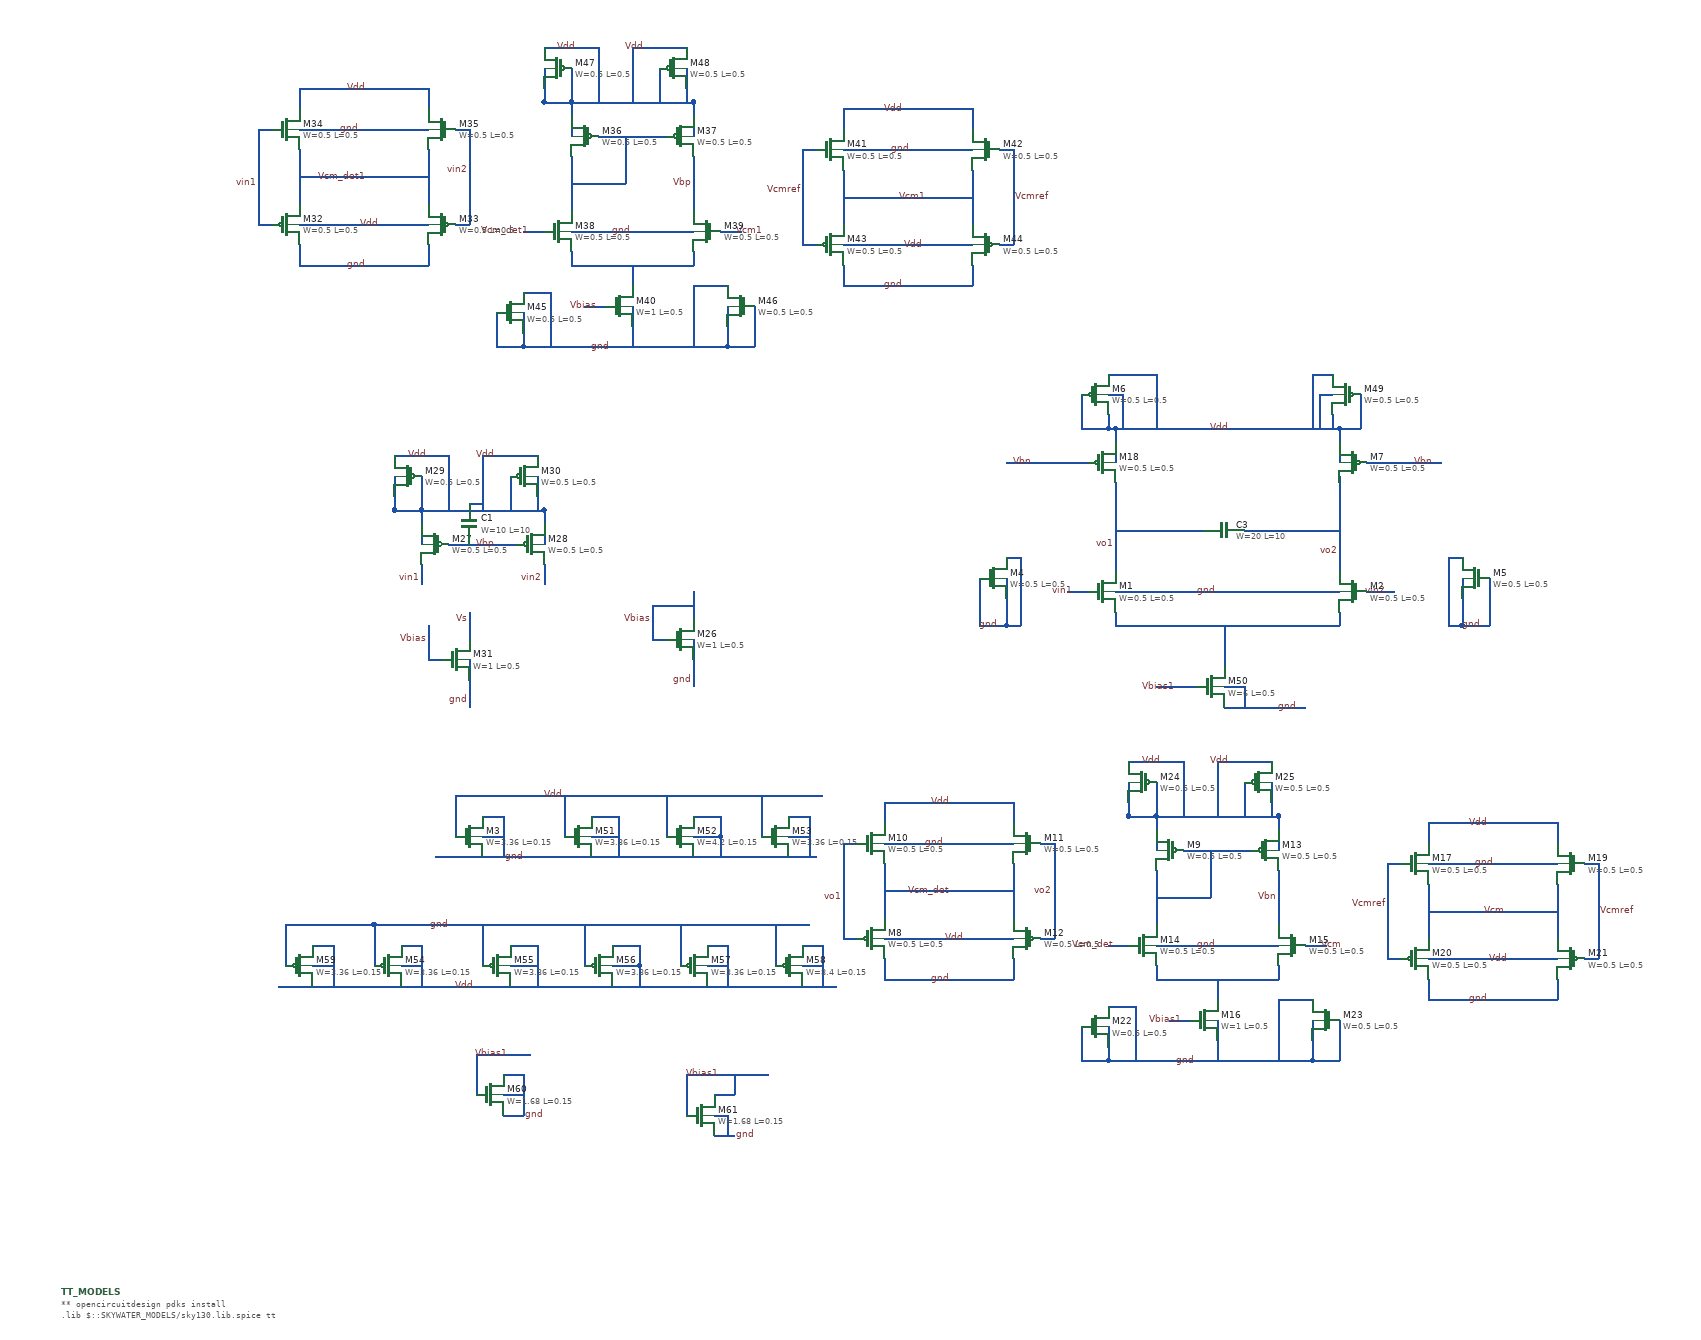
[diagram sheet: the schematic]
v {xschem version=3.4.4 file_version=1.2
}
G {}
K {}
V {}
S {}
E {}
N -2610 -900 -2610 -860 {
lab=Vbias}
N -2670 -830 -2650 -830 {
lab=Vbias}
N -2670 -880 -2670 -830 {
lab=Vbias}
N -2670 -880 -2610 -880 {
lab=Vbias}
N -2610 -800 -2610 -760 {
lab=gnd}
N -2610 -830 -2610 -790 {
lab=gnd}
N -3010 -1020 -3010 -1000 {
lab=Vdd}
N -2830 -1020 -2830 -1000 {
lab=Vdd}
N -2970 -970 -2870 -970 {
lab=Vbp}
N -3010 -1020 -2830 -1020 {
lab=Vdd}
N -3050 -1040 -3050 -1020 {
lab=Vdd}
N -3050 -1020 -2990 -1020 {
lab=Vdd}
N -2840 -1040 -2840 -1020 {
lab=Vdd}
N -3010 -1070 -3010 -1020 {
lab=Vdd}
N -2880 -1070 -2880 -1020 {
lab=Vdd}
N -3050 -1100 -2970 -1100 {
lab=Vdd}
N -2970 -1100 -2970 -1020 {
lab=Vdd}
N -2920 -1100 -2840 -1100 {
lab=Vdd}
N -2920 -1100 -2920 -1020 {
lab=Vdd}
N -3010 -1010 -3010 -970 {
lab=Vdd}
N -2830 -1020 -2830 -970 {
lab=Vdd}
N -3050 -1070 -3050 -1020 {
lab=Vdd}
N -2840 -1070 -2840 -1030 {
lab=Vdd}
N -3010 -940 -3010 -910 {
lab=vin1}
N -2830 -940 -2830 -910 {
lab=vin2}
N -2940 -870 -2940 -830 {
lab=Vs}
N -3000 -800 -2980 -800 {
lab=Vbias}
N -3000 -850 -3000 -800 {
lab=Vbias}
N -2940 -770 -2940 -730 {
lab=gnd}
N -2940 -800 -2940 -760 {
lab=gnd}
N -2940 -1030 -2920 -1030 {
lab=Vdd}
N -2790 -1540 -2790 -1460 {
lab=#net1}
N -2610 -1540 -2610 -1460 {
lab=Vbp}
N -2790 -1620 -2790 -1600 {
lab=Vdd}
N -2610 -1620 -2610 -1600 {
lab=Vdd}
N -2790 -1400 -2790 -1380 {
lab=#net2}
N -2790 -1380 -2610 -1380 {
lab=#net2}
N -2610 -1400 -2610 -1380 {
lab=#net2}
N -2750 -1570 -2650 -1570 {
lab=#net1}
N -2710 -1570 -2710 -1500 {
lab=#net1}
N -2790 -1500 -2710 -1500 {
lab=#net1}
N -3190 -1640 -3190 -1610 {
lab=Vdd}
N -3190 -1640 -3000 -1640 {
lab=Vdd}
N -3000 -1640 -3000 -1610 {
lab=Vdd}
N -3190 -1550 -3190 -1470 {
lab=Vcm_det1}
N -3000 -1550 -3000 -1470 {
lab=Vcm_det1}
N -3250 -1580 -3230 -1580 {
lab=vin1}
N -3250 -1580 -3250 -1440 {
lab=vin1}
N -3250 -1440 -3230 -1440 {
lab=vin1}
N -2960 -1580 -2940 -1580 {
lab=vin2}
N -2940 -1580 -2940 -1440 {
lab=vin2}
N -2960 -1440 -2940 -1440 {
lab=vin2}
N -2390 -1610 -2390 -1580 {
lab=Vdd}
N -2390 -1610 -2200 -1610 {
lab=Vdd}
N -2200 -1610 -2200 -1580 {
lab=Vdd}
N -2390 -1520 -2390 -1440 {
lab=Vcm1}
N -2200 -1520 -2200 -1440 {
lab=Vcm1}
N -2390 -1380 -2390 -1350 {
lab=gnd}
N -2200 -1380 -2200 -1350 {
lab=gnd}
N -2450 -1550 -2430 -1550 {
lab=Vcmref}
N -2450 -1550 -2450 -1410 {
lab=Vcmref}
N -2450 -1410 -2430 -1410 {
lab=Vcmref}
N -2160 -1550 -2140 -1550 {
lab=Vcmref}
N -2140 -1550 -2140 -1410 {
lab=Vcmref}
N -2160 -1410 -2140 -1410 {
lab=Vcmref}
N -2700 -1380 -2700 -1350 {
lab=#net2}
N -2700 -1290 -2700 -1260 {
lab=gnd}
N -3190 -1510 -3000 -1510 {
lab=Vcm_det1}
N -2390 -1480 -2200 -1480 {
lab=Vcm1}
N -2860 -1430 -2830 -1430 {
lab=Vcm_det1}
N -2570 -1430 -2540 -1430 {
lab=Vcm1}
N -2790 -1620 -2610 -1620 {
lab=Vdd}
N -2390 -1350 -2200 -1350 {
lab=gnd}
N -2860 -1280 -2860 -1260 {
lab=gnd}
N -2860 -1260 -2560 -1260 {
lab=gnd}
N -2560 -1290 -2560 -1260 {
lab=gnd}
N -2900 -1310 -2900 -1260 {
lab=gnd}
N -2900 -1260 -2860 -1260 {
lab=gnd}
N -2860 -1340 -2820 -1340 {
lab=gnd}
N -2820 -1340 -2820 -1260 {
lab=gnd}
N -2520 -1320 -2520 -1260 {
lab=gnd}
N -2560 -1260 -2520 -1260 {
lab=gnd}
N -2610 -1350 -2560 -1350 {
lab=gnd}
N -2610 -1350 -2610 -1260 {
lab=gnd}
N -2830 -1640 -2830 -1620 {
lab=Vdd}
N -2830 -1620 -2770 -1620 {
lab=Vdd}
N -2620 -1640 -2620 -1620 {
lab=Vdd}
N -2790 -1670 -2790 -1620 {
lab=Vdd}
N -2660 -1670 -2660 -1620 {
lab=Vdd}
N -2830 -1700 -2750 -1700 {
lab=Vdd}
N -2750 -1700 -2750 -1620 {
lab=Vdd}
N -2700 -1700 -2620 -1700 {
lab=Vdd}
N -2700 -1700 -2700 -1620 {
lab=Vdd}
N -3190 -1410 -3190 -1380 {
lab=gnd}
N -3190 -1380 -3000 -1380 {
lab=gnd}
N -3000 -1410 -3000 -1380 {
lab=gnd}
N -2790 -1610 -2790 -1570 {
lab=Vdd}
N -2610 -1620 -2610 -1570 {
lab=Vdd}
N -2830 -1670 -2830 -1620 {
lab=Vdd}
N -2620 -1670 -2620 -1630 {
lab=Vdd}
N -2860 -1310 -2860 -1270 {
lab=gnd}
N -2560 -1320 -2560 -1280 {
lab=gnd}
N -2700 -1320 -2700 -1280 {
lab=gnd}
N -3190 -1580 -3140 -1580 {
lab=gnd}
N -3070 -1580 -3000 -1580 {
lab=gnd}
N -3140 -1580 -3070 -1580 {
lab=gnd}
N -3190 -1440 -3000 -1440 {
lab=Vdd}
N -2390 -1550 -2200 -1550 {
lab=gnd}
N -2390 -1410 -2200 -1410 {
lab=Vdd}
N -2790 -1430 -2610 -1430 {
lab=gnd}
N -2770 -1320 -2740 -1320 {
lab=Vbias}
N -1990 -870 -1990 -850 {
lab=#net3}
N -1990 -850 -1810 -850 {
lab=#net3}
N -1660 -870 -1660 -850 {
lab=#net3}
N -1990 -1140 -1990 -1120 {
lab=Vdd}
N -1990 -1140 -1810 -1140 {
lab=Vdd}
N -1660 -1140 -1660 -1120 {
lab=Vdd}
N -1810 -1140 -1660 -1140 {
lab=Vdd}
N -1810 -850 -1660 -850 {
lab=#net3}
N -1990 -990 -1860 -990 {
lab=vo1}
N -1800 -990 -1660 -990 {
lab=vo2}
N -2150 -1090 -2030 -1090 {
lab=Vbn}
N -1620 -1090 -1510 -1090 {
lab=Vbn}
N -2060 -900 -2030 -900 {
lab=vin1}
N -1620 -900 -1580 -900 {
lab=vin2}
N -1990 -1000 -1990 -930 {
lab=vo1}
N -1660 -1000 -1660 -930 {
lab=vo2}
N -1660 -1070 -1660 -1000 {
lab=vo2}
N -1990 -1060 -1990 -1000 {
lab=vo1}
N -1830 -850 -1830 -790 {
lab=#net3}
N -2150 -890 -2150 -850 {
lab=gnd}
N -1480 -890 -1480 -850 {
lab=gnd}
N -2190 -920 -2190 -850 {
lab=gnd}
N -2190 -850 -2150 -850 {
lab=gnd}
N -2150 -950 -2130 -950 {
lab=gnd}
N -2130 -950 -2130 -850 {
lab=gnd}
N -2150 -920 -2150 -870 {
lab=gnd}
N -1500 -950 -1480 -950 {
lab=gnd}
N -1500 -950 -1500 -850 {
lab=gnd}
N -1480 -920 -1480 -870 {
lab=gnd}
N -1440 -920 -1440 -850 {
lab=gnd}
N -1480 -850 -1440 -850 {
lab=gnd}
N -2000 -1160 -2000 -1140 {
lab=Vdd}
N -2000 -1140 -1990 -1140 {
lab=Vdd}
N -1670 -1160 -1670 -1140 {
lab=Vdd}
N -2000 -1220 -1930 -1220 {
lab=Vdd}
N -1930 -1220 -1930 -1140 {
lab=Vdd}
N -1700 -1220 -1670 -1220 {
lab=Vdd}
N -1700 -1220 -1700 -1140 {
lab=Vdd}
N -2000 -1190 -1980 -1190 {
lab=Vdd}
N -1980 -1190 -1980 -1140 {
lab=Vdd}
N -1690 -1190 -1670 -1190 {
lab=Vdd}
N -1690 -1190 -1690 -1140 {
lab=Vdd}
N -1630 -1190 -1630 -1140 {
lab=Vdd}
N -1660 -1140 -1630 -1140 {
lab=Vdd}
N -2040 -1190 -2040 -1140 {
lab=Vdd}
N -2040 -1140 -2000 -1140 {
lab=Vdd}
N -1990 -1130 -1990 -1090 {
lab=Vdd}
N -1660 -1130 -1660 -1090 {
lab=Vdd}
N -1930 -490 -1930 -410 {
lab=#net4}
N -1750 -490 -1750 -410 {
lab=Vbn}
N -1930 -570 -1930 -550 {
lab=Vdd}
N -1750 -570 -1750 -550 {
lab=Vdd}
N -1930 -350 -1930 -330 {
lab=#net5}
N -1930 -330 -1750 -330 {
lab=#net5}
N -1750 -350 -1750 -330 {
lab=#net5}
N -1890 -520 -1790 -520 {
lab=#net4}
N -1850 -520 -1850 -450 {
lab=#net4}
N -1930 -450 -1850 -450 {
lab=#net4}
N -2330 -590 -2330 -560 {
lab=Vdd}
N -2330 -590 -2140 -590 {
lab=Vdd}
N -2140 -590 -2140 -560 {
lab=Vdd}
N -2330 -500 -2330 -420 {
lab=Vcm_det}
N -2140 -500 -2140 -420 {
lab=Vcm_det}
N -2390 -530 -2370 -530 {
lab=vo1}
N -2390 -530 -2390 -390 {
lab=vo1}
N -2390 -390 -2370 -390 {
lab=vo1}
N -2100 -530 -2080 -530 {
lab=vo2}
N -2080 -530 -2080 -390 {
lab=vo2}
N -2100 -390 -2080 -390 {
lab=vo2}
N -1530 -560 -1530 -530 {
lab=Vdd}
N -1530 -560 -1340 -560 {
lab=Vdd}
N -1340 -560 -1340 -530 {
lab=Vdd}
N -1530 -470 -1530 -390 {
lab=Vcm}
N -1340 -470 -1340 -390 {
lab=Vcm}
N -1530 -330 -1530 -300 {
lab=gnd}
N -1340 -330 -1340 -300 {
lab=gnd}
N -1590 -500 -1570 -500 {
lab=Vcmref}
N -1590 -500 -1590 -360 {
lab=Vcmref}
N -1590 -360 -1570 -360 {
lab=Vcmref}
N -1300 -500 -1280 -500 {
lab=Vcmref}
N -1280 -500 -1280 -360 {
lab=Vcmref}
N -1300 -360 -1280 -360 {
lab=Vcmref}
N -1840 -330 -1840 -300 {
lab=#net5}
N -1840 -240 -1840 -210 {
lab=gnd}
N -2330 -460 -2140 -460 {
lab=Vcm_det}
N -1530 -430 -1340 -430 {
lab=Vcm}
N -2000 -380 -1970 -380 {
lab=Vcm_det}
N -1710 -380 -1680 -380 {
lab=Vcm}
N -1930 -570 -1750 -570 {
lab=Vdd}
N -1530 -300 -1340 -300 {
lab=gnd}
N -2000 -230 -2000 -210 {
lab=gnd}
N -2000 -210 -1700 -210 {
lab=gnd}
N -1700 -240 -1700 -210 {
lab=gnd}
N -2040 -260 -2040 -210 {
lab=gnd}
N -2040 -210 -2000 -210 {
lab=gnd}
N -2000 -290 -1960 -290 {
lab=gnd}
N -1960 -290 -1960 -210 {
lab=gnd}
N -1660 -270 -1660 -210 {
lab=gnd}
N -1700 -210 -1660 -210 {
lab=gnd}
N -1750 -300 -1700 -300 {
lab=gnd}
N -1750 -300 -1750 -210 {
lab=gnd}
N -1970 -590 -1970 -570 {
lab=Vdd}
N -1970 -570 -1910 -570 {
lab=Vdd}
N -1760 -590 -1760 -570 {
lab=Vdd}
N -1930 -620 -1930 -570 {
lab=Vdd}
N -1800 -620 -1800 -570 {
lab=Vdd}
N -1970 -650 -1890 -650 {
lab=Vdd}
N -1890 -650 -1890 -570 {
lab=Vdd}
N -1840 -650 -1760 -650 {
lab=Vdd}
N -1840 -650 -1840 -570 {
lab=Vdd}
N -2330 -360 -2330 -330 {
lab=gnd}
N -2330 -330 -2140 -330 {
lab=gnd}
N -2140 -360 -2140 -330 {
lab=gnd}
N -1930 -560 -1930 -520 {
lab=Vdd}
N -1750 -570 -1750 -520 {
lab=Vdd}
N -1970 -620 -1970 -570 {
lab=Vdd}
N -1760 -620 -1760 -580 {
lab=Vdd}
N -2000 -260 -2000 -220 {
lab=gnd}
N -1700 -270 -1700 -230 {
lab=gnd}
N -1840 -270 -1840 -230 {
lab=gnd}
N -2330 -530 -2280 -530 {
lab=gnd}
N -2210 -530 -2140 -530 {
lab=gnd}
N -2280 -530 -2210 -530 {
lab=gnd}
N -2330 -390 -2140 -390 {
lab=Vdd}
N -1530 -500 -1340 -500 {
lab=gnd}
N -1530 -360 -1340 -360 {
lab=Vdd}
N -1930 -380 -1750 -380 {
lab=gnd}
N -1910 -270 -1880 -270 {
lab=Vbias1}
N -1990 -900 -1660 -900 {
lab=gnd}
N -1830 -730 -1710 -730 {
lab=gnd}
N -1830 -760 -1800 -760 {
lab=gnd}
N -1800 -760 -1800 -730 {
lab=gnd}
N -1930 -760 -1870 -760 {
lab=Vbias1}
N -2150 -850 -2130 -850 {
lab=gnd}
N -1500 -850 -1480 -850 {
lab=gnd}
N -2920 -570 -2890 -570 {
lab=gnd}
N -2890 -570 -2890 -510 {
lab=gnd}
N -2920 -510 -2890 -510 {
lab=gnd}
N -2920 -540 -2890 -540 {
lab=gnd}
N -2990 -510 -2540 -510 {
lab=gnd}
N -2960 -570 -2960 -540 {
lab=Vdd}
N -2800 -570 -2800 -540 {
lab=Vdd}
N -2960 -600 -2960 -570 {
lab=Vdd}
N -2960 -600 -2540 -600 {
lab=Vdd}
N -2800 -600 -2800 -570 {
lab=Vdd}
N -2760 -570 -2720 -570 {
lab=gnd}
N -2720 -570 -2720 -510 {
lab=gnd}
N -2760 -540 -2720 -540 {
lab=gnd}
N -2650 -600 -2650 -540 {
lab=Vdd}
N -2610 -540 -2570 -540 {
lab=gnd}
N -2570 -540 -2570 -510 {
lab=gnd}
N -2610 -570 -2570 -570 {
lab=gnd}
N -2570 -570 -2570 -540 {
lab=gnd}
N -2540 -600 -2420 -600 {
lab=Vdd}
N -2540 -510 -2430 -510 {
lab=gnd}
N -2510 -600 -2510 -540 {
lab=Vdd}
N -2470 -570 -2440 -570 {
lab=gnd}
N -2440 -570 -2440 -510 {
lab=gnd}
N -2470 -540 -2440 -540 {
lab=gnd}
N -3040 -380 -3010 -380 {
lab=Vdd}
N -3010 -380 -3010 -320 {
lab=Vdd}
N -3040 -320 -3010 -320 {
lab=Vdd}
N -3040 -350 -3010 -350 {
lab=Vdd}
N -3110 -320 -2660 -320 {
lab=Vdd}
N -3080 -380 -3080 -350 {
lab=gnd}
N -2920 -380 -2920 -350 {
lab=gnd}
N -3080 -410 -3080 -380 {
lab=gnd}
N -3080 -410 -2660 -410 {
lab=gnd}
N -2920 -410 -2920 -380 {
lab=gnd}
N -2880 -380 -2840 -380 {
lab=Vdd}
N -2840 -380 -2840 -320 {
lab=Vdd}
N -2880 -350 -2840 -350 {
lab=Vdd}
N -2770 -410 -2770 -350 {
lab=gnd}
N -2730 -350 -2690 -350 {
lab=Vdd}
N -2690 -350 -2690 -320 {
lab=Vdd}
N -2730 -380 -2690 -380 {
lab=Vdd}
N -2690 -380 -2690 -350 {
lab=Vdd}
N -2660 -410 -2540 -410 {
lab=gnd}
N -2660 -320 -2550 -320 {
lab=Vdd}
N -2630 -410 -2630 -350 {
lab=gnd}
N -2590 -380 -2560 -380 {
lab=Vdd}
N -2560 -380 -2560 -320 {
lab=Vdd}
N -2590 -350 -2560 -350 {
lab=Vdd}
N -2540 -410 -2440 -410 {
lab=gnd}
N -2550 -320 -2400 -320 {
lab=Vdd}
N -2450 -380 -2420 -380 {
lab=Vdd}
N -2420 -380 -2420 -320 {
lab=Vdd}
N -2450 -350 -2420 -350 {
lab=Vdd}
N -2490 -410 -2490 -350 {
lab=gnd}
N -3210 -410 -3080 -410 {
lab=gnd}
N -3220 -320 -3110 -320 {
lab=Vdd}
N -3210 -410 -3210 -350 {
lab=gnd}
N -3170 -380 -3140 -380 {
lab=Vdd}
N -3140 -380 -3140 -320 {
lab=Vdd}
N -3170 -350 -3140 -350 {
lab=Vdd}
N -2890 -190 -2860 -190 {
lab=gnd}
N -2860 -190 -2860 -130 {
lab=gnd}
N -2890 -130 -2860 -130 {
lab=gnd}
N -2890 -160 -2860 -160 {
lab=gnd}
N -2930 -190 -2930 -160 {
lab=Vbias1}
N -2930 -220 -2930 -190 {
lab=Vbias1}
N -2930 -220 -2850 -220 {
lab=Vbias1}
N -2580 -160 -2550 -160 {
lab=gnd}
N -2580 -100 -2550 -100 {
lab=gnd}
N -2620 -160 -2620 -130 {
lab=Vbias1}
N -2620 -190 -2620 -160 {
lab=Vbias1}
N -2620 -190 -2540 -190 {
lab=Vbias1}
N -2580 -130 -2560 -130 {}
N -2560 -130 -2560 -100 {}
N -2550 -190 -2550 -160 {}
N -2540 -190 -2500 -190 {}
C {devices/code.sym} -3540 130 0 0 {name=TT_MODELS
only_toplevel=true
format="tcleval( @value )"
value="
** opencircuitdesign pdks install
.lib $::SKYWATER_MODELS/sky130.lib.spice tt

"
spice_ignore=false}
C {devices/lab_wire.sym} -2670 -860 0 0 {name=p30 sig_type=std_logic lab=Vbias

}
C {sky130_fd_pr/nfet_01v8.sym} -2630 -830 0 0 {name=M26
L=0.5
W=1
nf=1 
mult=1
ad="'int((nf+1)/2) * W/nf * 0.29'" 
pd="'2*int((nf+1)/2) * (W/nf + 0.29)'"
as="'int((nf+2)/2) * W/nf * 0.29'" 
ps="'2*int((nf+2)/2) * (W/nf + 0.29)'"
nrd="'0.29 / W'" nrs="'0.29 / W'"
sa=0 sb=0 sd=0
model=nfet_01v8
spiceprefix=X
}
C {devices/lab_wire.sym} -2610 -770 0 0 {name=p31 sig_type=std_logic lab=gnd

}
C {sky130_fd_pr/pfet_01v8.sym} -2990 -970 0 1 {name=M27
L=0.5
W=0.5
nf=1
mult=1
ad="'int((nf+1)/2) * W/nf * 0.29'" 
pd="'2*int((nf+1)/2) * (W/nf + 0.29)'"
as="'int((nf+2)/2) * W/nf * 0.29'" 
ps="'2*int((nf+2)/2) * (W/nf + 0.29)'"
nrd="'0.29 / W'" nrs="'0.29 / W'"
sa=0 sb=0 sd=0
model=pfet_01v8
spiceprefix=X
}
C {sky130_fd_pr/pfet_01v8.sym} -2850 -970 0 0 {name=M28
L=0.5
W=0.5
nf=1
mult=1
ad="'int((nf+1)/2) * W/nf * 0.29'" 
pd="'2*int((nf+1)/2) * (W/nf + 0.29)'"
as="'int((nf+2)/2) * W/nf * 0.29'" 
ps="'2*int((nf+2)/2) * (W/nf + 0.29)'"
nrd="'0.29 / W'" nrs="'0.29 / W'"
sa=0 sb=0 sd=0
model=pfet_01v8
spiceprefix=X
}
C {sky130_fd_pr/pfet_01v8.sym} -3030 -1070 0 1 {name=M29
L=0.5
W=0.5
nf=1
mult=1
ad="'int((nf+1)/2) * W/nf * 0.29'" 
pd="'2*int((nf+1)/2) * (W/nf + 0.29)'"
as="'int((nf+2)/2) * W/nf * 0.29'" 
ps="'2*int((nf+2)/2) * (W/nf + 0.29)'"
nrd="'0.29 / W'" nrs="'0.29 / W'"
sa=0 sb=0 sd=0
model=pfet_01v8
spiceprefix=X
}
C {sky130_fd_pr/pfet_01v8.sym} -2860 -1070 0 0 {name=M30
L=0.5
W=0.5
nf=1
mult=1
ad="'int((nf+1)/2) * W/nf * 0.29'" 
pd="'2*int((nf+1)/2) * (W/nf + 0.29)'"
as="'int((nf+2)/2) * W/nf * 0.29'" 
ps="'2*int((nf+2)/2) * (W/nf + 0.29)'"
nrd="'0.29 / W'" nrs="'0.29 / W'"
sa=0 sb=0 sd=0
model=pfet_01v8
spiceprefix=X
}
C {devices/lab_wire.sym} -3000 -1100 0 0 {name=p33 sig_type=std_logic lab=Vdd




}
C {devices/lab_wire.sym} -2900 -1100 0 0 {name=p34 sig_type=std_logic lab=Vdd




}
C {devices/lab_wire.sym} -3000 -830 0 0 {name=p35 sig_type=std_logic lab=Vbias

}
C {sky130_fd_pr/nfet_01v8.sym} -2960 -800 0 0 {name=M31
L=0.5
W=1
nf=1 
mult=1
ad="'int((nf+1)/2) * W/nf * 0.29'" 
pd="'2*int((nf+1)/2) * (W/nf + 0.29)'"
as="'int((nf+2)/2) * W/nf * 0.29'" 
ps="'2*int((nf+2)/2) * (W/nf + 0.29)'"
nrd="'0.29 / W'" nrs="'0.29 / W'"
sa=0 sb=0 sd=0
model=nfet_01v8
spiceprefix=X
}
C {devices/lab_wire.sym} -2940 -740 0 0 {name=p36 sig_type=std_logic lab=gnd

}
C {devices/lab_wire.sym} -2940 -860 0 0 {name=p37 sig_type=std_logic lab=Vs

}
C {devices/lab_wire.sym} -3010 -920 0 0 {name=p38 sig_type=std_logic lab=vin1


}
C {devices/lab_wire.sym} -2830 -920 0 0 {name=p39 sig_type=std_logic lab=vin2

}
C {sky130_fd_pr/cap_mim_m3_1.sym} -2940 -1000 0 0 {name=C1 model=cap_mim_m3_1 W=10 L=10 MF=1 spiceprefix=X}
C {devices/lab_wire.sym} -3090 -1510 0 0 {name=p42 sig_type=std_logic lab=Vcm_det1



}
C {devices/lab_wire.sym} -2450 -1490 0 0 {name=p43 sig_type=std_logic lab=Vcmref



}
C {devices/lab_wire.sym} -2140 -1480 0 1 {name=p44 sig_type=std_logic lab=Vcmref



}
C {devices/lab_wire.sym} -2310 -1480 0 1 {name=p45 sig_type=std_logic lab=Vcm1




}
C {devices/lab_wire.sym} -2550 -1430 0 1 {name=p46 sig_type=std_logic lab=Vcm1




}
C {devices/lab_wire.sym} -2850 -1430 0 0 {name=p47 sig_type=std_logic lab=Vcm_det1



}
C {devices/lab_wire.sym} -2610 -1500 0 0 {name=p48 sig_type=std_logic lab=Vbp




}
C {sky130_fd_pr/pfet_01v8.sym} -3210 -1440 0 0 {name=M32
L=0.5
W=0.5
nf=1
mult=1
ad="'int((nf+1)/2) * W/nf * 0.29'" 
pd="'2*int((nf+1)/2) * (W/nf + 0.29)'"
as="'int((nf+2)/2) * W/nf * 0.29'" 
ps="'2*int((nf+2)/2) * (W/nf + 0.29)'"
nrd="'0.29 / W'" nrs="'0.29 / W'"
sa=0 sb=0 sd=0
model=pfet_01v8
spiceprefix=X
}
C {sky130_fd_pr/pfet_01v8.sym} -2980 -1440 0 1 {name=M33
L=0.5
W=0.5
nf=1
mult=1
ad="'int((nf+1)/2) * W/nf * 0.29'" 
pd="'2*int((nf+1)/2) * (W/nf + 0.29)'"
as="'int((nf+2)/2) * W/nf * 0.29'" 
ps="'2*int((nf+2)/2) * (W/nf + 0.29)'"
nrd="'0.29 / W'" nrs="'0.29 / W'"
sa=0 sb=0 sd=0
model=pfet_01v8
spiceprefix=X
}
C {sky130_fd_pr/nfet_01v8.sym} -3210 -1580 0 0 {name=M34
L=0.5
W=0.5
nf=1 
mult=1
ad="'int((nf+1)/2) * W/nf * 0.29'" 
pd="'2*int((nf+1)/2) * (W/nf + 0.29)'"
as="'int((nf+2)/2) * W/nf * 0.29'" 
ps="'2*int((nf+2)/2) * (W/nf + 0.29)'"
nrd="'0.29 / W'" nrs="'0.29 / W'"
sa=0 sb=0 sd=0
model=nfet_01v8
spiceprefix=X
}
C {sky130_fd_pr/nfet_01v8.sym} -2980 -1580 0 1 {name=M35
L=0.5
W=0.5
nf=1 
mult=1
ad="'int((nf+1)/2) * W/nf * 0.29'" 
pd="'2*int((nf+1)/2) * (W/nf + 0.29)'"
as="'int((nf+2)/2) * W/nf * 0.29'" 
ps="'2*int((nf+2)/2) * (W/nf + 0.29)'"
nrd="'0.29 / W'" nrs="'0.29 / W'"
sa=0 sb=0 sd=0
model=nfet_01v8
spiceprefix=X
}
C {sky130_fd_pr/pfet_01v8.sym} -2770 -1570 0 1 {name=M36
L=0.5
W=0.5
nf=1
mult=1
ad="'int((nf+1)/2) * W/nf * 0.29'" 
pd="'2*int((nf+1)/2) * (W/nf + 0.29)'"
as="'int((nf+2)/2) * W/nf * 0.29'" 
ps="'2*int((nf+2)/2) * (W/nf + 0.29)'"
nrd="'0.29 / W'" nrs="'0.29 / W'"
sa=0 sb=0 sd=0
model=pfet_01v8
spiceprefix=X
}
C {sky130_fd_pr/pfet_01v8.sym} -2630 -1570 0 0 {name=M37
L=0.5
W=0.5
nf=1
mult=1
ad="'int((nf+1)/2) * W/nf * 0.29'" 
pd="'2*int((nf+1)/2) * (W/nf + 0.29)'"
as="'int((nf+2)/2) * W/nf * 0.29'" 
ps="'2*int((nf+2)/2) * (W/nf + 0.29)'"
nrd="'0.29 / W'" nrs="'0.29 / W'"
sa=0 sb=0 sd=0
model=pfet_01v8
spiceprefix=X
}
C {sky130_fd_pr/nfet_01v8.sym} -2810 -1430 0 0 {name=M38
L=0.5
W=0.5
nf=1 
mult=1
ad="'int((nf+1)/2) * W/nf * 0.29'" 
pd="'2*int((nf+1)/2) * (W/nf + 0.29)'"
as="'int((nf+2)/2) * W/nf * 0.29'" 
ps="'2*int((nf+2)/2) * (W/nf + 0.29)'"
nrd="'0.29 / W'" nrs="'0.29 / W'"
sa=0 sb=0 sd=0
model=nfet_01v8
spiceprefix=X
}
C {sky130_fd_pr/nfet_01v8.sym} -2590 -1430 0 1 {name=M39
L=0.5
W=0.5
nf=1 
mult=1
ad="'int((nf+1)/2) * W/nf * 0.29'" 
pd="'2*int((nf+1)/2) * (W/nf + 0.29)'"
as="'int((nf+2)/2) * W/nf * 0.29'" 
ps="'2*int((nf+2)/2) * (W/nf + 0.29)'"
nrd="'0.29 / W'" nrs="'0.29 / W'"
sa=0 sb=0 sd=0
model=nfet_01v8
spiceprefix=X
}
C {sky130_fd_pr/nfet_01v8.sym} -2720 -1320 0 0 {name=M40
L=0.5
W=1
nf=1 
mult=1
ad="'int((nf+1)/2) * W/nf * 0.29'" 
pd="'2*int((nf+1)/2) * (W/nf + 0.29)'"
as="'int((nf+2)/2) * W/nf * 0.29'" 
ps="'2*int((nf+2)/2) * (W/nf + 0.29)'"
nrd="'0.29 / W'" nrs="'0.29 / W'"
sa=0 sb=0 sd=0
model=nfet_01v8
spiceprefix=X
}
C {sky130_fd_pr/nfet_01v8.sym} -2410 -1550 0 0 {name=M41
L=0.5
W=0.5
nf=1 
mult=1
ad="'int((nf+1)/2) * W/nf * 0.29'" 
pd="'2*int((nf+1)/2) * (W/nf + 0.29)'"
as="'int((nf+2)/2) * W/nf * 0.29'" 
ps="'2*int((nf+2)/2) * (W/nf + 0.29)'"
nrd="'0.29 / W'" nrs="'0.29 / W'"
sa=0 sb=0 sd=0
model=nfet_01v8
spiceprefix=X
}
C {sky130_fd_pr/nfet_01v8.sym} -2180 -1550 0 1 {name=M42
L=0.5
W=0.5
nf=1 
mult=1
ad="'int((nf+1)/2) * W/nf * 0.29'" 
pd="'2*int((nf+1)/2) * (W/nf + 0.29)'"
as="'int((nf+2)/2) * W/nf * 0.29'" 
ps="'2*int((nf+2)/2) * (W/nf + 0.29)'"
nrd="'0.29 / W'" nrs="'0.29 / W'"
sa=0 sb=0 sd=0
model=nfet_01v8
spiceprefix=X
}
C {sky130_fd_pr/pfet_01v8.sym} -2410 -1410 0 0 {name=M43
L=0.5
W=0.5
nf=1
mult=1
ad="'int((nf+1)/2) * W/nf * 0.29'" 
pd="'2*int((nf+1)/2) * (W/nf + 0.29)'"
as="'int((nf+2)/2) * W/nf * 0.29'" 
ps="'2*int((nf+2)/2) * (W/nf + 0.29)'"
nrd="'0.29 / W'" nrs="'0.29 / W'"
sa=0 sb=0 sd=0
model=pfet_01v8
spiceprefix=X
}
C {sky130_fd_pr/pfet_01v8.sym} -2180 -1410 0 1 {name=M44
L=0.5
W=0.5
nf=1
mult=1
ad="'int((nf+1)/2) * W/nf * 0.29'" 
pd="'2*int((nf+1)/2) * (W/nf + 0.29)'"
as="'int((nf+2)/2) * W/nf * 0.29'" 
ps="'2*int((nf+2)/2) * (W/nf + 0.29)'"
nrd="'0.29 / W'" nrs="'0.29 / W'"
sa=0 sb=0 sd=0
model=pfet_01v8
spiceprefix=X
}
C {sky130_fd_pr/nfet_01v8.sym} -2880 -1310 0 0 {name=M45
L=0.5
W=0.5
nf=1 
mult=1
ad="'int((nf+1)/2) * W/nf * 0.29'" 
pd="'2*int((nf+1)/2) * (W/nf + 0.29)'"
as="'int((nf+2)/2) * W/nf * 0.29'" 
ps="'2*int((nf+2)/2) * (W/nf + 0.29)'"
nrd="'0.29 / W'" nrs="'0.29 / W'"
sa=0 sb=0 sd=0
model=nfet_01v8
spiceprefix=X
}
C {sky130_fd_pr/nfet_01v8.sym} -2540 -1320 0 1 {name=M46
L=0.5
W=0.5
nf=1 
mult=1
ad="'int((nf+1)/2) * W/nf * 0.29'" 
pd="'2*int((nf+1)/2) * (W/nf + 0.29)'"
as="'int((nf+2)/2) * W/nf * 0.29'" 
ps="'2*int((nf+2)/2) * (W/nf + 0.29)'"
nrd="'0.29 / W'" nrs="'0.29 / W'"
sa=0 sb=0 sd=0
model=nfet_01v8
spiceprefix=X
}
C {sky130_fd_pr/pfet_01v8.sym} -2810 -1670 0 1 {name=M47
L=0.5
W=0.5
nf=1
mult=1
ad="'int((nf+1)/2) * W/nf * 0.29'" 
pd="'2*int((nf+1)/2) * (W/nf + 0.29)'"
as="'int((nf+2)/2) * W/nf * 0.29'" 
ps="'2*int((nf+2)/2) * (W/nf + 0.29)'"
nrd="'0.29 / W'" nrs="'0.29 / W'"
sa=0 sb=0 sd=0
model=pfet_01v8
spiceprefix=X
}
C {sky130_fd_pr/pfet_01v8.sym} -2640 -1670 0 0 {name=M48
L=0.5
W=0.5
nf=1
mult=1
ad="'int((nf+1)/2) * W/nf * 0.29'" 
pd="'2*int((nf+1)/2) * (W/nf + 0.29)'"
as="'int((nf+2)/2) * W/nf * 0.29'" 
ps="'2*int((nf+2)/2) * (W/nf + 0.29)'"
nrd="'0.29 / W'" nrs="'0.29 / W'"
sa=0 sb=0 sd=0
model=pfet_01v8
spiceprefix=X
}
C {devices/lab_wire.sym} -3090 -1640 0 0 {name=p49 sig_type=std_logic lab=Vdd




}
C {devices/lab_wire.sym} -2780 -1700 0 0 {name=p50 sig_type=std_logic lab=Vdd




}
C {devices/lab_wire.sym} -2300 -1610 0 0 {name=p51 sig_type=std_logic lab=Vdd




}
C {devices/lab_wire.sym} -3090 -1380 0 0 {name=p52 sig_type=std_logic lab=gnd





}
C {devices/lab_wire.sym} -2730 -1260 0 0 {name=p53 sig_type=std_logic lab=gnd





}
C {devices/lab_wire.sym} -2300 -1350 0 0 {name=p54 sig_type=std_logic lab=gnd





}
C {devices/lab_wire.sym} -2680 -1700 0 0 {name=p55 sig_type=std_logic lab=Vdd




}
C {devices/lab_wire.sym} -3070 -1440 0 0 {name=p56 sig_type=std_logic lab=Vdd




}
C {devices/lab_wire.sym} -3100 -1580 0 0 {name=p57 sig_type=std_logic lab=gnd





}
C {devices/lab_wire.sym} -2270 -1410 0 0 {name=p58 sig_type=std_logic lab=Vdd




}
C {devices/lab_wire.sym} -2290 -1550 0 0 {name=p59 sig_type=std_logic lab=gnd





}
C {devices/lab_wire.sym} -2700 -1430 0 0 {name=p60 sig_type=std_logic lab=gnd





}
C {devices/lab_wire.sym} -2750 -1320 0 0 {name=p61 sig_type=std_logic lab=Vbias

}
C {devices/lab_wire.sym} -3250 -1500 0 0 {name=p40 sig_type=std_logic lab=vin1

}
C {devices/lab_wire.sym} -2940 -1520 0 0 {name=p41 sig_type=std_logic lab=vin2

}
C {devices/lab_wire.sym} -2900 -970 0 0 {name=p62 sig_type=std_logic lab=Vbp




}
C {devices/lab_wire.sym} -1820 -1140 0 0 {name=p2 sig_type=std_logic lab=Vdd
}
C {devices/lab_wire.sym} -2050 -900 0 0 {name=p7 sig_type=std_logic lab=vin1

}
C {devices/lab_wire.sym} -1590 -900 0 0 {name=p8 sig_type=std_logic lab=vin2


}
C {devices/lab_wire.sym} -1990 -970 0 0 {name=p9 sig_type=std_logic lab=vo1

}
C {devices/lab_wire.sym} -1660 -960 0 0 {name=p10 sig_type=std_logic lab=vo2


}
C {devices/lab_wire.sym} -2110 -1090 0 0 {name=p20 sig_type=std_logic lab=Vbn




}
C {devices/lab_wire.sym} -1520 -1090 0 0 {name=p21 sig_type=std_logic lab=Vbn




}
C {sky130_fd_pr/nfet_01v8.sym} -2010 -900 0 0 {name=M1
L=0.5
W=0.5
nf=1 
mult=1
ad="'int((nf+1)/2) * W/nf * 0.29'" 
pd="'2*int((nf+1)/2) * (W/nf + 0.29)'"
as="'int((nf+2)/2) * W/nf * 0.29'" 
ps="'2*int((nf+2)/2) * (W/nf + 0.29)'"
nrd="'0.29 / W'" nrs="'0.29 / W'"
sa=0 sb=0 sd=0
model=nfet_01v8
spiceprefix=X
}
C {sky130_fd_pr/nfet_01v8.sym} -1640 -900 0 1 {name=M2
L=0.5
W=0.5
nf=1 
mult=1
ad="'int((nf+1)/2) * W/nf * 0.29'" 
pd="'2*int((nf+1)/2) * (W/nf + 0.29)'"
as="'int((nf+2)/2) * W/nf * 0.29'" 
ps="'2*int((nf+2)/2) * (W/nf + 0.29)'"
nrd="'0.29 / W'" nrs="'0.29 / W'"
sa=0 sb=0 sd=0
model=nfet_01v8
spiceprefix=X
}
C {sky130_fd_pr/cap_mim_m3_1.sym} -1830 -990 1 0 {name=C3 model=cap_mim_m3_1 W=20 L=10 MF=1 spiceprefix=X}
C {sky130_fd_pr/nfet_01v8.sym} -2170 -920 0 0 {name=M4
L=0.5
W=0.5
nf=1 
mult=1
ad="'int((nf+1)/2) * W/nf * 0.29'" 
pd="'2*int((nf+1)/2) * (W/nf + 0.29)'"
as="'int((nf+2)/2) * W/nf * 0.29'" 
ps="'2*int((nf+2)/2) * (W/nf + 0.29)'"
nrd="'0.29 / W'" nrs="'0.29 / W'"
sa=0 sb=0 sd=0
model=nfet_01v8
spiceprefix=X
}
C {sky130_fd_pr/nfet_01v8.sym} -1460 -920 0 1 {name=M5
L=0.5
W=0.5
nf=1 
mult=1
ad="'int((nf+1)/2) * W/nf * 0.29'" 
pd="'2*int((nf+1)/2) * (W/nf + 0.29)'"
as="'int((nf+2)/2) * W/nf * 0.29'" 
ps="'2*int((nf+2)/2) * (W/nf + 0.29)'"
nrd="'0.29 / W'" nrs="'0.29 / W'"
sa=0 sb=0 sd=0
model=nfet_01v8
spiceprefix=X
}
C {devices/lab_wire.sym} -2390 -450 0 0 {name=p11 sig_type=std_logic lab=vo1

}
C {devices/lab_wire.sym} -2080 -460 0 0 {name=p12 sig_type=std_logic lab=vo2


}
C {devices/lab_wire.sym} -2230 -460 0 0 {name=p13 sig_type=std_logic lab=Vcm_det



}
C {devices/lab_wire.sym} -1590 -440 0 0 {name=p14 sig_type=std_logic lab=Vcmref



}
C {devices/lab_wire.sym} -1280 -430 0 1 {name=p15 sig_type=std_logic lab=Vcmref



}
C {devices/lab_wire.sym} -1450 -430 0 1 {name=p17 sig_type=std_logic lab=Vcm




}
C {devices/lab_wire.sym} -1690 -380 0 1 {name=p16 sig_type=std_logic lab=Vcm




}
C {devices/lab_wire.sym} -1990 -380 0 0 {name=p18 sig_type=std_logic lab=Vcm_det



}
C {devices/lab_wire.sym} -1750 -450 0 0 {name=p19 sig_type=std_logic lab=Vbn




}
C {sky130_fd_pr/pfet_01v8.sym} -2350 -390 0 0 {name=M8
L=0.5
W=0.5
nf=1
mult=1
ad="'int((nf+1)/2) * W/nf * 0.29'" 
pd="'2*int((nf+1)/2) * (W/nf + 0.29)'"
as="'int((nf+2)/2) * W/nf * 0.29'" 
ps="'2*int((nf+2)/2) * (W/nf + 0.29)'"
nrd="'0.29 / W'" nrs="'0.29 / W'"
sa=0 sb=0 sd=0
model=pfet_01v8
spiceprefix=X
}
C {sky130_fd_pr/pfet_01v8.sym} -2120 -390 0 1 {name=M12
L=0.5
W=0.5
nf=1
mult=1
ad="'int((nf+1)/2) * W/nf * 0.29'" 
pd="'2*int((nf+1)/2) * (W/nf + 0.29)'"
as="'int((nf+2)/2) * W/nf * 0.29'" 
ps="'2*int((nf+2)/2) * (W/nf + 0.29)'"
nrd="'0.29 / W'" nrs="'0.29 / W'"
sa=0 sb=0 sd=0
model=pfet_01v8
spiceprefix=X
}
C {sky130_fd_pr/nfet_01v8.sym} -2350 -530 0 0 {name=M10
L=0.5
W=0.5
nf=1 
mult=1
ad="'int((nf+1)/2) * W/nf * 0.29'" 
pd="'2*int((nf+1)/2) * (W/nf + 0.29)'"
as="'int((nf+2)/2) * W/nf * 0.29'" 
ps="'2*int((nf+2)/2) * (W/nf + 0.29)'"
nrd="'0.29 / W'" nrs="'0.29 / W'"
sa=0 sb=0 sd=0
model=nfet_01v8
spiceprefix=X
}
C {sky130_fd_pr/nfet_01v8.sym} -2120 -530 0 1 {name=M11
L=0.5
W=0.5
nf=1 
mult=1
ad="'int((nf+1)/2) * W/nf * 0.29'" 
pd="'2*int((nf+1)/2) * (W/nf + 0.29)'"
as="'int((nf+2)/2) * W/nf * 0.29'" 
ps="'2*int((nf+2)/2) * (W/nf + 0.29)'"
nrd="'0.29 / W'" nrs="'0.29 / W'"
sa=0 sb=0 sd=0
model=nfet_01v8
spiceprefix=X
}
C {sky130_fd_pr/pfet_01v8.sym} -1910 -520 0 1 {name=M9
L=0.5
W=0.5
nf=1
mult=1
ad="'int((nf+1)/2) * W/nf * 0.29'" 
pd="'2*int((nf+1)/2) * (W/nf + 0.29)'"
as="'int((nf+2)/2) * W/nf * 0.29'" 
ps="'2*int((nf+2)/2) * (W/nf + 0.29)'"
nrd="'0.29 / W'" nrs="'0.29 / W'"
sa=0 sb=0 sd=0
model=pfet_01v8
spiceprefix=X
}
C {sky130_fd_pr/pfet_01v8.sym} -1770 -520 0 0 {name=M13
L=0.5
W=0.5
nf=1
mult=1
ad="'int((nf+1)/2) * W/nf * 0.29'" 
pd="'2*int((nf+1)/2) * (W/nf + 0.29)'"
as="'int((nf+2)/2) * W/nf * 0.29'" 
ps="'2*int((nf+2)/2) * (W/nf + 0.29)'"
nrd="'0.29 / W'" nrs="'0.29 / W'"
sa=0 sb=0 sd=0
model=pfet_01v8
spiceprefix=X
}
C {sky130_fd_pr/nfet_01v8.sym} -1950 -380 0 0 {name=M14
L=0.5
W=0.5
nf=1 
mult=1
ad="'int((nf+1)/2) * W/nf * 0.29'" 
pd="'2*int((nf+1)/2) * (W/nf + 0.29)'"
as="'int((nf+2)/2) * W/nf * 0.29'" 
ps="'2*int((nf+2)/2) * (W/nf + 0.29)'"
nrd="'0.29 / W'" nrs="'0.29 / W'"
sa=0 sb=0 sd=0
model=nfet_01v8
spiceprefix=X
}
C {sky130_fd_pr/nfet_01v8.sym} -1730 -380 0 1 {name=M15
L=0.5
W=0.5
nf=1 
mult=1
ad="'int((nf+1)/2) * W/nf * 0.29'" 
pd="'2*int((nf+1)/2) * (W/nf + 0.29)'"
as="'int((nf+2)/2) * W/nf * 0.29'" 
ps="'2*int((nf+2)/2) * (W/nf + 0.29)'"
nrd="'0.29 / W'" nrs="'0.29 / W'"
sa=0 sb=0 sd=0
model=nfet_01v8
spiceprefix=X
}
C {sky130_fd_pr/nfet_01v8.sym} -1860 -270 0 0 {name=M16
L=0.5
W=1
nf=1 
mult=1
ad="'int((nf+1)/2) * W/nf * 0.29'" 
pd="'2*int((nf+1)/2) * (W/nf + 0.29)'"
as="'int((nf+2)/2) * W/nf * 0.29'" 
ps="'2*int((nf+2)/2) * (W/nf + 0.29)'"
nrd="'0.29 / W'" nrs="'0.29 / W'"
sa=0 sb=0 sd=0
model=nfet_01v8
spiceprefix=X
}
C {sky130_fd_pr/nfet_01v8.sym} -1550 -500 0 0 {name=M17
L=0.5
W=0.5
nf=1 
mult=1
ad="'int((nf+1)/2) * W/nf * 0.29'" 
pd="'2*int((nf+1)/2) * (W/nf + 0.29)'"
as="'int((nf+2)/2) * W/nf * 0.29'" 
ps="'2*int((nf+2)/2) * (W/nf + 0.29)'"
nrd="'0.29 / W'" nrs="'0.29 / W'"
sa=0 sb=0 sd=0
model=nfet_01v8
spiceprefix=X
}
C {sky130_fd_pr/nfet_01v8.sym} -1320 -500 0 1 {name=M19
L=0.5
W=0.5
nf=1 
mult=1
ad="'int((nf+1)/2) * W/nf * 0.29'" 
pd="'2*int((nf+1)/2) * (W/nf + 0.29)'"
as="'int((nf+2)/2) * W/nf * 0.29'" 
ps="'2*int((nf+2)/2) * (W/nf + 0.29)'"
nrd="'0.29 / W'" nrs="'0.29 / W'"
sa=0 sb=0 sd=0
model=nfet_01v8
spiceprefix=X
}
C {sky130_fd_pr/pfet_01v8.sym} -1550 -360 0 0 {name=M20
L=0.5
W=0.5
nf=1
mult=1
ad="'int((nf+1)/2) * W/nf * 0.29'" 
pd="'2*int((nf+1)/2) * (W/nf + 0.29)'"
as="'int((nf+2)/2) * W/nf * 0.29'" 
ps="'2*int((nf+2)/2) * (W/nf + 0.29)'"
nrd="'0.29 / W'" nrs="'0.29 / W'"
sa=0 sb=0 sd=0
model=pfet_01v8
spiceprefix=X
}
C {sky130_fd_pr/pfet_01v8.sym} -1320 -360 0 1 {name=M21
L=0.5
W=0.5
nf=1
mult=1
ad="'int((nf+1)/2) * W/nf * 0.29'" 
pd="'2*int((nf+1)/2) * (W/nf + 0.29)'"
as="'int((nf+2)/2) * W/nf * 0.29'" 
ps="'2*int((nf+2)/2) * (W/nf + 0.29)'"
nrd="'0.29 / W'" nrs="'0.29 / W'"
sa=0 sb=0 sd=0
model=pfet_01v8
spiceprefix=X
}
C {sky130_fd_pr/nfet_01v8.sym} -2020 -260 0 0 {name=M22
L=0.5
W=0.5
nf=1 
mult=1
ad="'int((nf+1)/2) * W/nf * 0.29'" 
pd="'2*int((nf+1)/2) * (W/nf + 0.29)'"
as="'int((nf+2)/2) * W/nf * 0.29'" 
ps="'2*int((nf+2)/2) * (W/nf + 0.29)'"
nrd="'0.29 / W'" nrs="'0.29 / W'"
sa=0 sb=0 sd=0
model=nfet_01v8
spiceprefix=X
}
C {sky130_fd_pr/nfet_01v8.sym} -1680 -270 0 1 {name=M23
L=0.5
W=0.5
nf=1 
mult=1
ad="'int((nf+1)/2) * W/nf * 0.29'" 
pd="'2*int((nf+1)/2) * (W/nf + 0.29)'"
as="'int((nf+2)/2) * W/nf * 0.29'" 
ps="'2*int((nf+2)/2) * (W/nf + 0.29)'"
nrd="'0.29 / W'" nrs="'0.29 / W'"
sa=0 sb=0 sd=0
model=nfet_01v8
spiceprefix=X
}
C {sky130_fd_pr/pfet_01v8.sym} -1950 -620 0 1 {name=M24
L=0.5
W=0.5
nf=1
mult=1
ad="'int((nf+1)/2) * W/nf * 0.29'" 
pd="'2*int((nf+1)/2) * (W/nf + 0.29)'"
as="'int((nf+2)/2) * W/nf * 0.29'" 
ps="'2*int((nf+2)/2) * (W/nf + 0.29)'"
nrd="'0.29 / W'" nrs="'0.29 / W'"
sa=0 sb=0 sd=0
model=pfet_01v8
spiceprefix=X
}
C {sky130_fd_pr/pfet_01v8.sym} -1780 -620 0 0 {name=M25
L=0.5
W=0.5
nf=1
mult=1
ad="'int((nf+1)/2) * W/nf * 0.29'" 
pd="'2*int((nf+1)/2) * (W/nf + 0.29)'"
as="'int((nf+2)/2) * W/nf * 0.29'" 
ps="'2*int((nf+2)/2) * (W/nf + 0.29)'"
nrd="'0.29 / W'" nrs="'0.29 / W'"
sa=0 sb=0 sd=0
model=pfet_01v8
spiceprefix=X
}
C {devices/lab_wire.sym} -2230 -590 0 0 {name=p3 sig_type=std_logic lab=Vdd




}
C {devices/lab_wire.sym} -1920 -650 0 0 {name=p4 sig_type=std_logic lab=Vdd




}
C {devices/lab_wire.sym} -1440 -560 0 0 {name=p5 sig_type=std_logic lab=Vdd




}
C {devices/lab_wire.sym} -2230 -330 0 0 {name=p6 sig_type=std_logic lab=gnd





}
C {devices/lab_wire.sym} -1870 -210 0 0 {name=p22 sig_type=std_logic lab=gnd





}
C {devices/lab_wire.sym} -1440 -300 0 0 {name=p23 sig_type=std_logic lab=gnd





}
C {devices/lab_wire.sym} -1820 -650 0 0 {name=p24 sig_type=std_logic lab=Vdd




}
C {devices/lab_wire.sym} -2210 -390 0 0 {name=p25 sig_type=std_logic lab=Vdd




}
C {devices/lab_wire.sym} -2240 -530 0 0 {name=p26 sig_type=std_logic lab=gnd





}
C {devices/lab_wire.sym} -1410 -360 0 0 {name=p27 sig_type=std_logic lab=Vdd




}
C {devices/lab_wire.sym} -1430 -500 0 0 {name=p28 sig_type=std_logic lab=gnd





}
C {devices/lab_wire.sym} -1840 -380 0 0 {name=p29 sig_type=std_logic lab=gnd





}
C {devices/lab_wire.sym} -1890 -270 0 0 {name=p63 sig_type=std_logic lab=Vbias1

}
C {sky130_fd_pr/pfet_01v8_lvt.sym} -2010 -1090 0 0 {name=M18
L=0.5
W=0.5
nf=1
mult=1
ad="'int((nf+1)/2) * W/nf * 0.29'" 
pd="'2*int((nf+1)/2) * (W/nf + 0.29)'"
as="'int((nf+2)/2) * W/nf * 0.29'" 
ps="'2*int((nf+2)/2) * (W/nf + 0.29)'"
nrd="'0.29 / W'" nrs="'0.29 / W'"
sa=0 sb=0 sd=0
model=pfet_01v8_lvt
spiceprefix=X
}
C {sky130_fd_pr/pfet_01v8_lvt.sym} -2020 -1190 0 0 {name=M6
L=0.5
W=0.5
nf=1
mult=1
ad="'int((nf+1)/2) * W/nf * 0.29'" 
pd="'2*int((nf+1)/2) * (W/nf + 0.29)'"
as="'int((nf+2)/2) * W/nf * 0.29'" 
ps="'2*int((nf+2)/2) * (W/nf + 0.29)'"
nrd="'0.29 / W'" nrs="'0.29 / W'"
sa=0 sb=0 sd=0
model=pfet_01v8_lvt
spiceprefix=X
}
C {sky130_fd_pr/pfet_01v8_lvt.sym} -1640 -1090 0 1 {name=M7
L=0.5
W=0.5
nf=1
mult=1
ad="'int((nf+1)/2) * W/nf * 0.29'" 
pd="'2*int((nf+1)/2) * (W/nf + 0.29)'"
as="'int((nf+2)/2) * W/nf * 0.29'" 
ps="'2*int((nf+2)/2) * (W/nf + 0.29)'"
nrd="'0.29 / W'" nrs="'0.29 / W'"
sa=0 sb=0 sd=0
model=pfet_01v8_lvt
spiceprefix=X
}
C {sky130_fd_pr/pfet_01v8_lvt.sym} -1650 -1190 0 1 {name=M49
L=0.5
W=0.5
nf=1
mult=1
ad="'int((nf+1)/2) * W/nf * 0.29'" 
pd="'2*int((nf+1)/2) * (W/nf + 0.29)'"
as="'int((nf+2)/2) * W/nf * 0.29'" 
ps="'2*int((nf+2)/2) * (W/nf + 0.29)'"
nrd="'0.29 / W'" nrs="'0.29 / W'"
sa=0 sb=0 sd=0
model=pfet_01v8_lvt
spiceprefix=X
}
C {devices/lab_wire.sym} -1840 -900 0 0 {name=p64 sig_type=std_logic lab=gnd

}
C {sky130_fd_pr/nfet_01v8.sym} -1850 -760 0 0 {name=M50
L=0.5
W=6
nf=6 
mult=1
ad="'int((nf+1)/2) * W/nf * 0.29'" 
pd="'2*int((nf+1)/2) * (W/nf + 0.29)'"
as="'int((nf+2)/2) * W/nf * 0.29'" 
ps="'2*int((nf+2)/2) * (W/nf + 0.29)'"
nrd="'0.29 / W'" nrs="'0.29 / W'"
sa=0 sb=0 sd=0
model=nfet_01v8
spiceprefix=X
}
C {devices/lab_wire.sym} -1720 -730 0 0 {name=p65 sig_type=std_logic lab=gnd

}
C {devices/lab_wire.sym} -1900 -760 0 0 {name=p66 sig_type=std_logic lab=Vbias1

}
C {devices/lab_wire.sym} -2160 -850 0 0 {name=p67 sig_type=std_logic lab=gnd

}
C {devices/lab_wire.sym} -1450 -850 0 0 {name=p68 sig_type=std_logic lab=gnd

}
C {sky130_fd_pr/nfet_01v8.sym} -2940 -540 0 0 {name=M3
L=0.15
W=3.36
nf=8 
mult=1
ad="'int((nf+1)/2) * W/nf * 0.29'" 
pd="'2*int((nf+1)/2) * (W/nf + 0.29)'"
as="'int((nf+2)/2) * W/nf * 0.29'" 
ps="'2*int((nf+2)/2) * (W/nf + 0.29)'"
nrd="'0.29 / W'" nrs="'0.29 / W'"
sa=0 sb=0 sd=0
model=nfet_01v8
spiceprefix=X
}
C {devices/lab_wire.sym} -2890 -510 0 1 {name=p1 sig_type=std_logic lab=gnd

}
C {devices/lab_wire.sym} -2800 -600 0 0 {name=p32 sig_type=std_logic lab=Vdd




}
C {sky130_fd_pr/nfet_01v8.sym} -2780 -540 0 0 {name=M51
L=0.15
W=3.36
nf=8 
mult=1
ad="'int((nf+1)/2) * W/nf * 0.29'" 
pd="'2*int((nf+1)/2) * (W/nf + 0.29)'"
as="'int((nf+2)/2) * W/nf * 0.29'" 
ps="'2*int((nf+2)/2) * (W/nf + 0.29)'"
nrd="'0.29 / W'" nrs="'0.29 / W'"
sa=0 sb=0 sd=0
model=nfet_01v8
spiceprefix=X
}
C {sky130_fd_pr/nfet_01v8.sym} -2630 -540 0 0 {name=M52
L=0.15
W=4.2
nf=10
mult=1
ad="'int((nf+1)/2) * W/nf * 0.29'" 
pd="'2*int((nf+1)/2) * (W/nf + 0.29)'"
as="'int((nf+2)/2) * W/nf * 0.29'" 
ps="'2*int((nf+2)/2) * (W/nf + 0.29)'"
nrd="'0.29 / W'" nrs="'0.29 / W'"
sa=0 sb=0 sd=0
model=nfet_01v8
spiceprefix=X
}
C {sky130_fd_pr/nfet_01v8.sym} -2490 -540 0 0 {name=M53
L=0.15
W=3.36
nf=8
mult=1
ad="'int((nf+1)/2) * W/nf * 0.29'" 
pd="'2*int((nf+1)/2) * (W/nf + 0.29)'"
as="'int((nf+2)/2) * W/nf * 0.29'" 
ps="'2*int((nf+2)/2) * (W/nf + 0.29)'"
nrd="'0.29 / W'" nrs="'0.29 / W'"
sa=0 sb=0 sd=0
model=nfet_01v8
spiceprefix=X
}
C {devices/lab_wire.sym} -3000 -410 0 1 {name=p69 sig_type=std_logic lab=gnd

}
C {devices/lab_wire.sym} -2930 -320 0 0 {name=p70 sig_type=std_logic lab=Vdd




}
C {sky130_fd_pr/pfet_01v8.sym} -3060 -350 0 0 {name=M54
L=0.15
W=3.36
nf=8
mult=1
ad="'int((nf+1)/2) * W/nf * 0.29'" 
pd="'2*int((nf+1)/2) * (W/nf + 0.29)'"
as="'int((nf+2)/2) * W/nf * 0.29'" 
ps="'2*int((nf+2)/2) * (W/nf + 0.29)'"
nrd="'0.29 / W'" nrs="'0.29 / W'"
sa=0 sb=0 sd=0
model=pfet_01v8
spiceprefix=X
}
C {sky130_fd_pr/pfet_01v8.sym} -2900 -350 0 0 {name=M55
L=0.15
W=3.36
nf=8
mult=1
ad="'int((nf+1)/2) * W/nf * 0.29'" 
pd="'2*int((nf+1)/2) * (W/nf + 0.29)'"
as="'int((nf+2)/2) * W/nf * 0.29'" 
ps="'2*int((nf+2)/2) * (W/nf + 0.29)'"
nrd="'0.29 / W'" nrs="'0.29 / W'"
sa=0 sb=0 sd=0
model=pfet_01v8
spiceprefix=X
}
C {sky130_fd_pr/pfet_01v8.sym} -2750 -350 0 0 {name=M56
L=0.15
W=3.36
nf=8
mult=1
ad="'int((nf+1)/2) * W/nf * 0.29'" 
pd="'2*int((nf+1)/2) * (W/nf + 0.29)'"
as="'int((nf+2)/2) * W/nf * 0.29'" 
ps="'2*int((nf+2)/2) * (W/nf + 0.29)'"
nrd="'0.29 / W'" nrs="'0.29 / W'"
sa=0 sb=0 sd=0
model=pfet_01v8
spiceprefix=X
}
C {sky130_fd_pr/pfet_01v8.sym} -2610 -350 0 0 {name=M57
L=0.15
W=3.36
nf=8
mult=1
ad="'int((nf+1)/2) * W/nf * 0.29'" 
pd="'2*int((nf+1)/2) * (W/nf + 0.29)'"
as="'int((nf+2)/2) * W/nf * 0.29'" 
ps="'2*int((nf+2)/2) * (W/nf + 0.29)'"
nrd="'0.29 / W'" nrs="'0.29 / W'"
sa=0 sb=0 sd=0
model=pfet_01v8
spiceprefix=X
}
C {sky130_fd_pr/pfet_01v8.sym} -2470 -350 0 0 {name=M58
L=0.15
W=8.4
nf=20
mult=1
ad="'int((nf+1)/2) * W/nf * 0.29'" 
pd="'2*int((nf+1)/2) * (W/nf + 0.29)'"
as="'int((nf+2)/2) * W/nf * 0.29'" 
ps="'2*int((nf+2)/2) * (W/nf + 0.29)'"
nrd="'0.29 / W'" nrs="'0.29 / W'"
sa=0 sb=0 sd=0
model=pfet_01v8
spiceprefix=X
}
C {sky130_fd_pr/pfet_01v8.sym} -3190 -350 0 0 {name=M59
L=0.15
W=3.36
nf=8
mult=1
ad="'int((nf+1)/2) * W/nf * 0.29'" 
pd="'2*int((nf+1)/2) * (W/nf + 0.29)'"
as="'int((nf+2)/2) * W/nf * 0.29'" 
ps="'2*int((nf+2)/2) * (W/nf + 0.29)'"
nrd="'0.29 / W'" nrs="'0.29 / W'"
sa=0 sb=0 sd=0
model=pfet_01v8
spiceprefix=X
}
C {sky130_fd_pr/nfet_01v8.sym} -2910 -160 0 0 {name=M60
L=0.15
W=1.68
nf=4
mult=1
ad="'int((nf+1)/2) * W/nf * 0.29'" 
pd="'2*int((nf+1)/2) * (W/nf + 0.29)'"
as="'int((nf+2)/2) * W/nf * 0.29'" 
ps="'2*int((nf+2)/2) * (W/nf + 0.29)'"
nrd="'0.29 / W'" nrs="'0.29 / W'"
sa=0 sb=0 sd=0
model=nfet_01v8
spiceprefix=X
}
C {devices/lab_wire.sym} -2860 -130 0 1 {name=p71 sig_type=std_logic lab=gnd

}
C {devices/lab_wire.sym} -2880 -220 0 0 {name=p72 sig_type=std_logic lab=Vbias1

}
C {sky130_fd_pr/nfet_01v8.sym} -2600 -130 0 0 {name=M61
L=0.15
W=1.68
nf=4
mult=1
ad="'int((nf+1)/2) * W/nf * 0.29'" 
pd="'2*int((nf+1)/2) * (W/nf + 0.29)'"
as="'int((nf+2)/2) * W/nf * 0.29'" 
ps="'2*int((nf+2)/2) * (W/nf + 0.29)'"
nrd="'0.29 / W'" nrs="'0.29 / W'"
sa=0 sb=0 sd=0
model=nfet_01v8
spiceprefix=X
}
C {devices/lab_wire.sym} -2550 -100 0 1 {name=p73 sig_type=std_logic lab=gnd

}
C {devices/lab_wire.sym} -2570 -190 0 0 {name=p74 sig_type=std_logic lab=Vbias1

}
